VERSION 5.7 ;
  NOWIREEXTENSIONATPIN ON ;
  DIVIDERCHAR "/" ;
  BUSBITCHARS "[]" ;
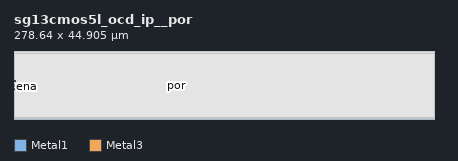
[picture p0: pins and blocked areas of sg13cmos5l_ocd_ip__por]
MACRO sg13cmos5l_ocd_ip__por
  CLASS BLOCK ;
  FOREIGN sg13cmos5l_ocd_ip__por ;
  ORIGIN -25.810 4.055 ;
  SIZE 278.640 BY 44.905 ;
  PIN vdd1v2
    ANTENNAGATEAREA 0.914000 ;
    ANTENNADIFFAREA 65.153397 ;
    PORT
      LAYER Metal1 ;
        RECT 26.175 20.615 26.925 21.270 ;
    END
  END vdd1v2
  PIN ena
    ANTENNAGATEAREA 0.733200 ;
    ANTENNADIFFAREA 0.608400 ;
    PORT
      LAYER Metal3 ;
        RECT 26.165 17.380 26.805 18.020 ;
    END
  END ena
  PIN por_unbuf
    ANTENNAGATEAREA 3.510000 ;
    ANTENNADIFFAREA 0.252000 ;
    PORT
      LAYER Metal3 ;
        RECT 133.340 19.200 133.980 19.840 ;
    END
  END por_unbuf
  PIN vss
    ANTENNAGATEAREA 1.369200 ;
    ANTENNADIFFAREA 245.987244 ;
    PORT
      LAYER Metal1 ;
        RECT 26.195 15.285 27.430 16.150 ;
    END
  END vss
  PIN porb
    ANTENNADIFFAREA 5.654400 ;
    PORT
      LAYER Metal3 ;
        RECT 133.335 16.785 133.975 17.425 ;
    END
  END porb
  PIN por
    ANTENNADIFFAREA 5.654400 ;
    PORT
      LAYER Metal3 ;
        RECT 133.340 18.015 133.980 18.655 ;
    END
  END por
  OBS
      LAYER GatPoly ;
        RECT 26.120 -3.745 134.270 40.540 ;
      LAYER Metal1 ;
        RECT 26.165 21.450 304.270 40.655 ;
        RECT 27.105 20.435 304.270 21.450 ;
        RECT 26.165 16.330 304.270 20.435 ;
        RECT 27.610 15.105 304.270 16.330 ;
        RECT 26.165 -3.875 304.270 15.105 ;
      LAYER Metal2 ;
        RECT 26.165 -3.875 304.270 40.655 ;
      LAYER Metal3 ;
        RECT 26.150 20.050 304.450 40.665 ;
        RECT 26.150 18.990 133.130 20.050 ;
        RECT 134.190 18.990 304.450 20.050 ;
        RECT 26.150 18.865 304.450 18.990 ;
        RECT 26.150 18.230 133.130 18.865 ;
        RECT 27.015 17.805 133.130 18.230 ;
        RECT 134.190 17.805 304.450 18.865 ;
        RECT 27.015 17.635 304.450 17.805 ;
        RECT 27.015 17.170 133.125 17.635 ;
        RECT 26.150 16.575 133.125 17.170 ;
        RECT 134.185 16.575 304.450 17.635 ;
        RECT 26.150 -3.890 304.450 16.575 ;
      LAYER Metal4 ;
        RECT 26.360 -2.930 304.450 39.420 ;
  END
END sg13cmos5l_ocd_ip__por
END LIBRARY

